VERSION 5.8 ;
BUSBITCHARS "[]" ;
DIVIDERCHAR "/" ;
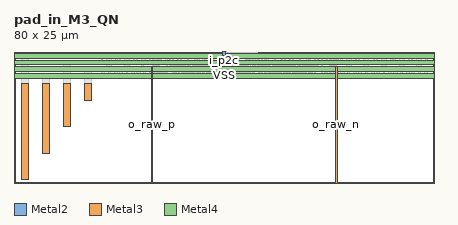
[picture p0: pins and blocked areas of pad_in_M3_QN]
MACRO pad_in_M3_QN
  CLASS BLOCK ;
  FOREIGN pad_in_M3_QN 0 0 ;
  ORIGIN 0.000 0.000 ;
  SIZE 80.000 BY 25.000 ;
  SYMMETRY X Y R90 ;
  PIN i_p2c
    DIRECTION INPUT ;
    PORT
      LAYER Metal2 ;
        RECT 39.725 24.200 40.225 25.000 ;
    END
  END i_p2c
  PIN i_clk_p
    DIRECTION INPUT ;
    PORT
      LAYER Metal3 ;
        RECT 9.500 10.700 10.700 19.000 ;
      LAYER Metal4 ;
        RECT 0.000 22.500 80.000 23.300 ;
    END
  END i_clk_p
  PIN i_clk_n
    DIRECTION INPUT ;
    PORT
      LAYER Metal3 ;
        RECT 13.500 15.700 14.700 19.000 ;
      LAYER Metal4 ;
        RECT 0.000 21.300 80.000 22.100 ;
    END
  END i_clk_n
  PIN o_raw_p
    DIRECTION OUTPUT ;
    PORT
      LAYER Metal3 ;
        RECT 26.110 0.000 26.410 22.275 ;
    END
  END o_raw_p
  PIN o_raw_n
    DIRECTION OUTPUT ;
    PORT
      LAYER Metal3 ;
        RECT 61.270 0.000 61.570 22.275 ;
    END
  END o_raw_n
  PIN VDD
    DIRECTION INOUT ;
    USE POWER ;
    PORT
      LAYER Metal3 ;
        RECT 1.500 0.700 2.700 19.000 ;
      LAYER Metal4 ;
        RECT 0.000 23.780 80.000 24.580 ;
    END
  END VDD
  PIN VSS
    DIRECTION INOUT ;
    USE GROUND ;
    PORT
      LAYER Metal3 ;
        RECT 5.500 5.700 6.700 19.000 ;
      LAYER Metal4 ;
        RECT 0.000 20.000 80.000 20.800 ;
    END
  END VSS
  OBS
    LAYER Metal1 ;
      RECT 16.480 20.180 79.840 20.620 ;
      RECT 47.790 22.140 48.560 22.440 ;
      RECT 16.480 23.960 79.840 24.400 ;
      RECT 63.300 21.875 64.235 23.960 ;
      RECT 65.615 20.620 66.250 21.390 ;
      RECT 68.025 20.620 68.635 21.390 ;
      RECT 68.975 20.620 69.610 21.390 ;
      RECT 71.385 20.620 71.995 21.390 ;
      RECT 72.335 20.620 72.970 21.390 ;
      RECT 74.745 20.620 75.355 21.390 ;
      RECT 75.695 20.620 76.330 21.390 ;
      RECT 78.105 20.620 78.715 21.390 ;
      RECT 66.970 20.620 67.275 21.430 ;
      RECT 70.330 20.620 70.635 21.430 ;
      RECT 73.690 20.620 73.995 21.430 ;
      RECT 77.050 20.620 77.355 21.430 ;
      RECT 64.665 21.390 64.915 22.210 ;
      RECT 65.960 21.390 66.250 22.210 ;
      RECT 68.025 21.390 68.275 22.210 ;
      RECT 69.320 21.390 69.610 22.210 ;
      RECT 71.385 21.390 71.635 22.210 ;
      RECT 72.680 21.390 72.970 22.210 ;
      RECT 74.745 21.390 74.995 22.210 ;
      RECT 76.040 21.390 76.330 22.210 ;
      RECT 78.105 21.390 78.355 22.210 ;
      RECT 64.665 20.620 65.275 21.390 ;
      RECT 65.025 22.610 65.285 23.960 ;
      RECT 65.625 22.605 65.885 23.960 ;
      RECT 66.660 21.875 67.595 23.960 ;
      RECT 68.385 22.610 68.645 23.960 ;
      RECT 68.985 22.605 69.245 23.960 ;
      RECT 70.020 21.875 70.955 23.960 ;
      RECT 71.745 22.610 72.005 23.960 ;
      RECT 72.345 22.605 72.605 23.960 ;
      RECT 73.380 21.875 74.315 23.960 ;
      RECT 75.105 22.610 75.365 23.960 ;
      RECT 75.705 22.605 75.965 23.960 ;
      RECT 76.740 21.875 77.675 23.960 ;
      RECT 78.465 22.610 78.725 23.960 ;
      RECT 50.380 21.695 50.540 22.415 ;
      RECT 55.180 21.695 55.340 22.415 ;
      RECT 56.000 22.340 56.260 22.415 ;
      RECT 55.180 22.415 56.260 22.540 ;
      RECT 54.360 22.540 56.260 22.590 ;
      RECT 56.000 22.590 56.260 22.600 ;
      RECT 49.220 22.140 50.200 22.300 ;
      RECT 54.020 22.140 55.000 22.300 ;
      RECT 58.490 21.610 58.680 22.550 ;
      RECT 48.740 21.940 48.900 23.040 ;
      RECT 53.540 21.940 53.700 23.040 ;
      RECT 61.075 22.240 61.335 22.395 ;
      RECT 51.640 21.820 51.800 22.800 ;
      RECT 52.480 22.140 53.360 22.440 ;
      RECT 56.440 21.820 56.600 22.800 ;
      RECT 57.280 22.140 58.060 22.440 ;
      RECT 60.055 22.565 60.315 23.530 ;
      RECT 61.075 22.565 61.335 23.530 ;
      RECT 56.790 22.440 57.090 22.740 ;
      RECT 58.490 22.550 59.295 22.820 ;
      RECT 59.035 22.820 59.295 23.170 ;
      RECT 56.280 22.800 56.600 22.940 ;
      RECT 56.280 22.940 56.540 23.700 ;
      RECT 60.055 22.395 61.335 22.565 ;
      RECT 57.280 22.440 57.440 23.340 ;
      RECT 57.220 23.340 57.480 23.700 ;
      RECT 57.780 23.400 58.040 23.960 ;
      RECT 58.525 23.040 58.785 23.960 ;
      RECT 59.545 22.480 59.805 23.960 ;
      RECT 60.565 22.890 60.825 23.960 ;
      RECT 61.585 22.515 61.845 23.960 ;
      RECT 62.265 22.605 62.525 23.960 ;
      RECT 49.540 23.200 49.840 23.270 ;
      RECT 54.360 22.510 54.620 22.540 ;
      RECT 54.340 22.970 54.640 23.040 ;
      RECT 53.540 23.040 54.640 23.200 ;
      RECT 54.340 23.200 54.640 23.270 ;
      RECT 49.560 22.510 49.820 22.540 ;
      RECT 50.380 22.415 51.460 22.540 ;
      RECT 49.560 22.540 51.460 22.590 ;
      RECT 54.360 22.590 55.340 22.700 ;
      RECT 54.360 22.700 54.620 22.770 ;
      RECT 51.480 22.800 51.800 22.940 ;
      RECT 51.480 22.940 51.740 23.700 ;
      RECT 54.800 22.700 55.340 22.840 ;
      RECT 52.480 22.440 52.640 23.340 ;
      RECT 52.420 23.340 52.680 23.700 ;
      RECT 51.200 22.590 51.460 22.600 ;
      RECT 49.220 22.300 49.380 22.540 ;
      RECT 49.080 22.540 49.380 22.860 ;
      RECT 49.560 22.590 50.540 22.700 ;
      RECT 54.020 22.300 54.180 22.540 ;
      RECT 53.880 22.540 54.180 22.860 ;
      RECT 48.180 23.130 48.440 23.960 ;
      RECT 49.560 23.450 49.820 23.960 ;
      RECT 50.940 23.130 51.200 23.960 ;
      RECT 52.980 23.130 53.240 23.960 ;
      RECT 54.360 23.450 54.620 23.960 ;
      RECT 55.740 23.130 56.000 23.960 ;
      RECT 49.560 22.700 49.820 22.770 ;
      RECT 50.000 22.700 50.540 22.840 ;
      RECT 51.990 22.440 52.290 22.740 ;
      RECT 51.200 22.340 51.460 22.415 ;
      RECT 49.540 22.970 49.840 23.040 ;
      RECT 48.740 23.040 49.840 23.200 ;
      RECT 50.270 21.350 50.540 21.695 ;
      RECT 55.070 21.350 55.340 21.695 ;
      RECT 48.310 21.680 48.570 21.780 ;
      RECT 48.310 21.780 48.900 21.940 ;
      RECT 54.050 21.350 54.210 22.140 ;
      RECT 54.740 22.040 55.000 22.140 ;
      RECT 48.670 21.050 48.970 21.500 ;
      RECT 51.360 21.030 51.620 21.520 ;
      RECT 51.360 21.520 51.660 21.620 ;
      RECT 51.360 21.620 51.800 21.820 ;
      RECT 50.720 21.915 51.020 22.215 ;
      RECT 49.250 21.350 49.410 22.140 ;
      RECT 53.110 21.680 53.370 21.780 ;
      RECT 52.380 21.030 52.640 21.490 ;
      RECT 52.480 21.490 52.640 22.140 ;
      RECT 53.110 21.780 53.700 21.940 ;
      RECT 49.940 22.040 50.200 22.140 ;
      RECT 55.520 21.915 55.820 22.215 ;
      RECT 51.870 20.620 52.130 21.390 ;
      RECT 53.470 20.850 55.790 21.050 ;
      RECT 48.180 20.620 48.440 21.500 ;
      RECT 52.980 20.620 53.240 21.500 ;
      RECT 53.470 21.050 53.770 21.500 ;
      RECT 55.530 21.050 55.790 21.650 ;
      RECT 49.710 21.240 49.970 21.690 ;
      RECT 54.510 21.240 54.770 21.690 ;
      RECT 48.670 20.850 50.990 21.050 ;
      RECT 50.730 21.050 50.990 21.650 ;
      RECT 59.650 21.940 60.400 22.200 ;
      RECT 63.610 20.620 63.915 21.430 ;
      RECT 59.105 21.010 59.705 21.270 ;
      RECT 56.160 21.030 56.420 21.520 ;
      RECT 56.160 21.520 56.460 21.620 ;
      RECT 56.160 21.620 56.600 21.820 ;
      RECT 60.565 20.620 60.825 21.270 ;
      RECT 58.930 21.875 59.380 22.285 ;
      RECT 58.490 21.040 58.835 21.450 ;
      RECT 56.670 20.620 56.930 21.390 ;
      RECT 62.255 20.620 62.890 21.390 ;
      RECT 57.180 21.030 57.440 21.490 ;
      RECT 57.280 21.490 57.440 22.140 ;
      RECT 58.490 21.450 59.815 21.610 ;
      RECT 61.585 20.620 61.845 21.610 ;
      RECT 62.600 21.390 62.890 22.210 ;
      RECT 59.650 21.610 59.815 21.940 ;
      RECT 60.055 21.045 60.315 21.465 ;
      RECT 61.075 21.005 61.335 21.465 ;
      RECT 60.055 21.465 61.335 21.625 ;
      RECT 61.075 21.625 61.335 21.925 ;
      RECT 59.275 20.620 59.535 21.010 ;
      RECT 61.075 21.925 61.760 22.240 ;
      RECT 31.420 22.415 32.500 22.540 ;
      RECT 31.420 22.540 33.320 22.590 ;
      RECT 31.890 20.850 34.210 21.050 ;
      RECT 33.980 21.940 34.140 23.040 ;
      RECT 38.780 21.940 38.940 23.040 ;
      RECT 43.580 21.940 43.740 23.040 ;
      RECT 45.370 22.105 47.110 22.405 ;
      RECT 40.190 22.440 40.490 22.740 ;
      RECT 32.340 21.695 32.500 22.415 ;
      RECT 37.140 21.695 37.300 22.415 ;
      RECT 34.320 22.140 35.200 22.440 ;
      RECT 35.880 21.820 36.040 22.800 ;
      RECT 39.120 22.140 40.000 22.440 ;
      RECT 40.680 21.820 40.840 22.800 ;
      RECT 43.920 22.140 44.690 22.440 ;
      RECT 44.980 21.820 45.140 22.570 ;
      RECT 47.340 21.820 47.500 22.570 ;
      RECT 41.940 21.695 42.100 22.415 ;
      RECT 32.680 22.140 33.660 22.300 ;
      RECT 37.480 22.140 38.460 22.300 ;
      RECT 42.280 22.140 43.260 22.300 ;
      RECT 42.640 22.970 42.940 23.040 ;
      RECT 44.530 22.440 44.690 23.320 ;
      RECT 44.530 23.320 44.860 23.470 ;
      RECT 44.600 23.470 44.860 23.700 ;
      RECT 42.640 23.040 43.740 23.200 ;
      RECT 44.870 22.570 45.170 22.690 ;
      RECT 44.870 22.690 45.370 22.870 ;
      RECT 45.110 22.870 45.370 23.700 ;
      RECT 42.640 23.200 42.940 23.270 ;
      RECT 47.310 22.570 47.610 22.690 ;
      RECT 47.110 22.690 47.610 22.870 ;
      RECT 47.110 22.870 47.370 23.700 ;
      RECT 47.790 22.440 47.950 23.320 ;
      RECT 47.620 23.320 47.950 23.470 ;
      RECT 47.620 23.470 47.880 23.700 ;
      RECT 41.020 22.340 41.280 22.415 ;
      RECT 43.100 22.300 43.260 22.540 ;
      RECT 41.020 22.415 42.100 22.540 ;
      RECT 42.660 22.510 42.920 22.540 ;
      RECT 41.020 22.540 42.920 22.590 ;
      RECT 41.020 22.590 41.280 22.600 ;
      RECT 41.940 22.590 42.920 22.700 ;
      RECT 42.660 22.700 42.920 22.770 ;
      RECT 41.940 22.700 42.480 22.840 ;
      RECT 41.280 23.130 41.540 23.960 ;
      RECT 42.660 23.450 42.920 23.960 ;
      RECT 44.040 23.130 44.300 23.960 ;
      RECT 45.650 23.410 45.910 23.960 ;
      RECT 46.570 23.410 46.830 23.960 ;
      RECT 43.100 22.540 43.400 22.860 ;
      RECT 40.680 22.800 41.000 22.940 ;
      RECT 40.740 22.940 41.000 23.700 ;
      RECT 39.840 22.440 40.000 23.340 ;
      RECT 39.800 23.340 40.060 23.700 ;
      RECT 37.860 22.510 38.120 22.540 ;
      RECT 36.220 22.540 38.120 22.590 ;
      RECT 36.220 22.590 36.480 22.600 ;
      RECT 37.140 22.590 38.120 22.700 ;
      RECT 37.860 22.700 38.120 22.770 ;
      RECT 37.140 22.700 37.680 22.840 ;
      RECT 33.040 23.040 34.140 23.200 ;
      RECT 33.040 23.200 33.340 23.270 ;
      RECT 33.060 22.510 33.320 22.540 ;
      RECT 37.840 22.970 38.140 23.040 ;
      RECT 32.340 22.590 33.320 22.700 ;
      RECT 33.060 22.700 33.320 22.770 ;
      RECT 32.340 22.700 32.880 22.840 ;
      RECT 36.220 22.340 36.480 22.415 ;
      RECT 33.040 22.970 33.340 23.040 ;
      RECT 33.060 23.450 33.320 23.960 ;
      RECT 34.440 23.130 34.700 23.960 ;
      RECT 36.480 23.130 36.740 23.960 ;
      RECT 37.860 23.450 38.120 23.960 ;
      RECT 39.240 23.130 39.500 23.960 ;
      RECT 37.840 23.040 38.940 23.200 ;
      RECT 35.040 22.440 35.200 23.340 ;
      RECT 35.000 23.340 35.260 23.700 ;
      RECT 35.390 22.440 35.690 22.740 ;
      RECT 35.880 22.800 36.200 22.940 ;
      RECT 35.940 22.940 36.200 23.700 ;
      RECT 33.500 22.300 33.660 22.540 ;
      RECT 33.500 22.540 33.800 22.860 ;
      RECT 36.220 22.415 37.300 22.540 ;
      RECT 38.300 22.300 38.460 22.540 ;
      RECT 38.300 22.540 38.600 22.860 ;
      RECT 37.840 23.200 38.140 23.270 ;
      RECT 36.690 20.850 39.010 21.050 ;
      RECT 39.840 21.030 40.100 21.490 ;
      RECT 35.550 20.620 35.810 21.390 ;
      RECT 39.840 21.490 40.000 22.140 ;
      RECT 38.710 21.050 39.010 21.500 ;
      RECT 36.690 21.050 36.950 21.650 ;
      RECT 32.910 21.240 33.170 21.690 ;
      RECT 37.140 21.350 37.410 21.695 ;
      RECT 39.110 21.680 39.370 21.780 ;
      RECT 38.780 21.780 39.370 21.940 ;
      RECT 35.040 21.030 35.300 21.490 ;
      RECT 35.040 21.490 35.200 22.140 ;
      RECT 36.660 21.915 36.960 22.215 ;
      RECT 33.910 21.050 34.210 21.500 ;
      RECT 34.440 20.620 34.700 21.500 ;
      RECT 39.240 20.620 39.500 21.500 ;
      RECT 32.680 22.040 32.940 22.140 ;
      RECT 33.470 21.350 33.630 22.140 ;
      RECT 32.340 21.350 32.610 21.695 ;
      RECT 37.710 21.240 37.970 21.690 ;
      RECT 36.060 21.030 36.320 21.520 ;
      RECT 37.480 22.040 37.740 22.140 ;
      RECT 38.270 21.350 38.430 22.140 ;
      RECT 36.020 21.520 36.320 21.620 ;
      RECT 35.880 21.620 36.320 21.820 ;
      RECT 34.310 21.680 34.570 21.780 ;
      RECT 33.980 21.780 34.570 21.940 ;
      RECT 40.820 21.520 41.120 21.620 ;
      RECT 40.680 21.620 41.120 21.820 ;
      RECT 43.580 21.780 44.170 21.940 ;
      RECT 43.510 21.050 43.810 21.500 ;
      RECT 47.650 21.030 47.910 21.350 ;
      RECT 47.650 21.350 47.950 21.460 ;
      RECT 47.790 21.460 47.950 22.140 ;
      RECT 41.490 21.050 41.750 21.650 ;
      RECT 44.570 21.030 44.830 21.350 ;
      RECT 44.530 21.350 44.830 21.460 ;
      RECT 44.530 21.460 44.690 22.140 ;
      RECT 41.460 21.915 41.760 22.215 ;
      RECT 47.140 20.620 47.400 21.390 ;
      RECT 42.510 21.240 42.770 21.690 ;
      RECT 40.350 20.620 40.610 21.390 ;
      RECT 44.040 20.620 44.300 21.500 ;
      RECT 45.590 21.030 45.850 21.520 ;
      RECT 45.550 21.520 45.850 21.620 ;
      RECT 41.940 21.350 42.210 21.695 ;
      RECT 44.980 21.620 45.850 21.820 ;
      RECT 41.490 20.850 43.810 21.050 ;
      RECT 45.080 20.620 45.340 21.390 ;
      RECT 43.910 21.680 44.170 21.780 ;
      RECT 40.860 21.030 41.120 21.520 ;
      RECT 46.630 21.030 46.890 21.520 ;
      RECT 46.630 21.520 46.930 21.620 ;
      RECT 42.280 22.040 42.540 22.140 ;
      RECT 43.070 21.350 43.230 22.140 ;
      RECT 46.630 21.620 47.500 21.820 ;
      RECT 31.860 21.915 32.160 22.215 ;
      RECT 30.590 22.440 30.890 22.740 ;
      RECT 20.360 21.390 20.650 22.210 ;
      RECT 30.240 21.030 30.500 21.490 ;
      RECT 30.240 21.490 30.400 22.140 ;
      RECT 29.620 22.140 30.400 22.440 ;
      RECT 30.240 22.440 30.400 23.340 ;
      RECT 30.200 23.340 30.460 23.700 ;
      RECT 28.145 20.620 28.405 21.010 ;
      RECT 31.260 21.030 31.520 21.520 ;
      RECT 26.855 20.620 27.115 21.270 ;
      RECT 18.010 20.620 18.315 21.430 ;
      RECT 21.370 20.620 21.675 21.430 ;
      RECT 27.975 21.010 28.575 21.270 ;
      RECT 24.265 21.870 24.605 22.620 ;
      RECT 16.665 22.605 16.925 23.960 ;
      RECT 17.700 21.875 18.635 23.960 ;
      RECT 19.425 22.610 19.685 23.960 ;
      RECT 20.025 22.605 20.285 23.960 ;
      RECT 21.060 21.875 21.995 23.960 ;
      RECT 22.785 22.610 23.045 23.960 ;
      RECT 23.330 22.620 23.600 23.960 ;
      RECT 24.265 22.620 24.990 23.960 ;
      RECT 25.835 22.515 26.095 23.960 ;
      RECT 26.855 22.890 27.115 23.960 ;
      RECT 27.875 22.480 28.135 23.960 ;
      RECT 28.895 23.040 29.155 23.960 ;
      RECT 29.640 23.400 29.900 23.960 ;
      RECT 31.680 23.130 31.940 23.960 ;
      RECT 31.220 21.520 31.520 21.620 ;
      RECT 31.080 21.620 31.520 21.820 ;
      RECT 31.080 21.820 31.240 22.800 ;
      RECT 31.080 22.800 31.400 22.940 ;
      RECT 31.140 22.940 31.400 23.700 ;
      RECT 22.425 21.390 22.675 22.210 ;
      RECT 28.845 21.040 29.190 21.450 ;
      RECT 27.865 21.450 29.190 21.610 ;
      RECT 27.865 21.610 28.030 21.940 ;
      RECT 31.420 22.340 31.680 22.415 ;
      RECT 27.280 21.940 28.030 22.200 ;
      RECT 31.890 21.050 32.150 21.650 ;
      RECT 23.330 20.620 24.055 21.335 ;
      RECT 24.710 20.620 24.990 21.335 ;
      RECT 29.000 21.610 29.190 22.550 ;
      RECT 26.345 21.005 26.605 21.465 ;
      RECT 27.365 21.045 27.625 21.465 ;
      RECT 16.655 20.620 17.290 21.390 ;
      RECT 19.065 20.620 19.675 21.390 ;
      RECT 25.835 20.620 26.095 21.610 ;
      RECT 20.015 20.620 20.650 21.390 ;
      RECT 23.730 21.335 24.055 22.205 ;
      RECT 17.000 21.390 17.290 22.210 ;
      RECT 19.065 21.390 19.315 22.210 ;
      RECT 26.345 21.465 27.625 21.625 ;
      RECT 26.345 21.625 26.605 21.925 ;
      RECT 25.920 21.925 26.605 22.240 ;
      RECT 26.345 22.240 26.605 22.395 ;
      RECT 26.345 22.395 27.625 22.565 ;
      RECT 26.345 22.565 26.605 23.530 ;
      RECT 27.365 22.565 27.625 23.530 ;
      RECT 28.385 22.550 29.190 22.820 ;
      RECT 28.385 22.820 28.645 23.170 ;
      RECT 31.420 22.590 31.680 22.600 ;
      RECT 22.425 20.620 23.035 21.390 ;
      RECT 28.300 21.875 28.750 22.285 ;
      RECT 30.750 20.620 31.010 21.390 ;
    LAYER Metal2 ;
      RECT 46.635 21.595 49.390 21.815 ;
      RECT 56.365 20.205 56.755 20.595 ;
      RECT 62.685 20.205 63.075 20.595 ;
      RECT 64.385 20.205 64.775 20.595 ;
      RECT 66.045 20.205 66.435 20.595 ;
      RECT 67.745 20.205 68.135 20.595 ;
      RECT 69.405 20.205 69.795 20.595 ;
      RECT 71.105 20.205 71.495 20.595 ;
      RECT 72.765 20.205 73.155 20.595 ;
      RECT 74.465 20.205 74.855 20.595 ;
      RECT 76.125 20.205 76.515 20.595 ;
      RECT 77.825 20.205 78.215 20.595 ;
      RECT 49.690 20.250 49.990 20.550 ;
      RECT 49.690 20.550 49.890 21.360 ;
      RECT 49.690 21.360 49.990 21.645 ;
      RECT 54.490 20.250 54.790 20.550 ;
      RECT 54.490 20.550 54.690 21.360 ;
      RECT 54.490 21.360 54.790 21.645 ;
      RECT 51.565 20.205 51.955 20.595 ;
      RECT 49.170 21.815 49.390 21.920 ;
      RECT 49.170 21.920 51.015 22.120 ;
      RECT 50.725 22.120 51.015 22.210 ;
      RECT 51.365 21.525 51.655 21.595 ;
      RECT 51.365 21.595 54.190 21.815 ;
      RECT 53.970 21.815 54.190 21.920 ;
      RECT 53.970 21.920 55.815 22.120 ;
      RECT 55.525 22.120 55.815 22.210 ;
      RECT 57.760 21.320 58.060 21.420 ;
      RECT 56.165 21.525 56.455 21.595 ;
      RECT 57.760 21.420 59.255 21.595 ;
      RECT 56.165 21.595 59.255 21.720 ;
      RECT 56.165 21.720 58.060 21.815 ;
      RECT 59.055 21.720 59.255 22.225 ;
      RECT 61.225 21.885 61.615 22.275 ;
      RECT 51.990 22.440 52.290 22.540 ;
      RECT 49.080 22.540 52.290 22.740 ;
      RECT 49.080 22.740 49.380 22.840 ;
      RECT 56.790 22.440 57.090 22.540 ;
      RECT 53.880 22.540 57.090 22.740 ;
      RECT 53.880 22.740 54.180 22.840 ;
      RECT 49.545 22.975 50.410 23.265 ;
      RECT 54.345 22.975 55.210 23.265 ;
      RECT 50.365 23.985 50.755 24.375 ;
      RECT 55.165 23.985 55.555 24.375 ;
      RECT 62.685 23.985 63.075 24.375 ;
      RECT 64.385 23.985 64.775 24.375 ;
      RECT 66.045 23.985 66.435 24.375 ;
      RECT 67.745 23.985 68.135 24.375 ;
      RECT 69.405 23.985 69.795 24.375 ;
      RECT 71.105 23.985 71.495 24.375 ;
      RECT 72.765 23.985 73.155 24.375 ;
      RECT 74.465 23.985 74.855 24.375 ;
      RECT 76.125 23.985 76.515 24.375 ;
      RECT 77.825 23.985 78.215 24.375 ;
      RECT 20.445 20.205 20.835 20.595 ;
      RECT 32.890 20.250 33.190 20.550 ;
      RECT 32.990 20.550 33.190 21.360 ;
      RECT 32.890 21.360 33.190 21.645 ;
      RECT 37.690 20.250 37.990 20.550 ;
      RECT 37.790 20.550 37.990 21.360 ;
      RECT 37.690 21.360 37.990 21.645 ;
      RECT 29.620 21.320 29.920 21.420 ;
      RECT 28.425 21.420 29.920 21.595 ;
      RECT 31.225 21.525 31.515 21.595 ;
      RECT 28.425 21.595 31.515 21.720 ;
      RECT 29.620 21.720 31.515 21.815 ;
      RECT 28.425 21.720 28.625 22.225 ;
      RECT 42.490 20.250 42.790 20.550 ;
      RECT 42.590 20.550 42.790 21.360 ;
      RECT 42.490 21.360 42.790 21.645 ;
      RECT 22.145 20.205 22.535 20.595 ;
      RECT 30.925 20.205 31.315 20.595 ;
      RECT 35.725 20.205 36.115 20.595 ;
      RECT 26.065 21.885 26.455 22.275 ;
      RECT 40.525 20.205 40.915 20.595 ;
      RECT 30.590 22.440 30.890 22.540 ;
      RECT 30.590 22.540 33.800 22.740 ;
      RECT 33.500 22.740 33.800 22.840 ;
      RECT 35.390 22.440 35.690 22.540 ;
      RECT 35.390 22.540 38.600 22.740 ;
      RECT 38.300 22.740 38.600 22.840 ;
      RECT 40.190 22.440 40.490 22.540 ;
      RECT 40.190 22.540 43.400 22.740 ;
      RECT 43.100 22.740 43.400 22.840 ;
      RECT 45.085 20.205 45.475 20.595 ;
      RECT 47.005 20.205 47.395 20.595 ;
      RECT 36.025 21.525 36.315 21.595 ;
      RECT 33.490 21.595 36.315 21.815 ;
      RECT 33.490 21.815 33.710 21.920 ;
      RECT 31.865 21.920 33.710 22.120 ;
      RECT 32.470 22.975 33.335 23.265 ;
      RECT 37.270 22.975 38.135 23.265 ;
      RECT 42.070 22.975 42.935 23.265 ;
      RECT 31.865 22.120 32.155 22.210 ;
      RECT 40.825 21.525 41.115 21.595 ;
      RECT 17.085 23.985 17.475 24.375 ;
      RECT 18.785 23.985 19.175 24.375 ;
      RECT 20.445 23.985 20.835 24.375 ;
      RECT 22.145 23.985 22.535 24.375 ;
      RECT 32.125 23.985 32.515 24.375 ;
      RECT 36.925 23.985 37.315 24.375 ;
      RECT 41.725 23.985 42.115 24.375 ;
      RECT 45.085 23.985 45.475 24.375 ;
      RECT 47.005 23.985 47.395 24.375 ;
      RECT 38.290 21.595 41.115 21.815 ;
      RECT 38.290 21.815 38.510 21.920 ;
      RECT 36.665 21.920 38.510 22.120 ;
      RECT 36.665 22.120 36.955 22.210 ;
      RECT 45.555 21.525 45.845 21.595 ;
      RECT 43.090 21.595 45.845 21.815 ;
      RECT 43.090 21.815 43.310 21.920 ;
      RECT 41.465 21.920 43.310 22.120 ;
      RECT 41.465 22.120 41.755 22.210 ;
      RECT 46.635 21.525 46.925 21.595 ;
      RECT 17.085 20.205 17.475 20.595 ;
      RECT 18.785 20.205 19.175 20.595 ;
      RECT 40.225 24.200 40.410 24.600 ;
      RECT 46.090 21.955 46.390 24.600 ;
      RECT 40.225 24.600 46.390 24.900 ;
      RECT 40.225 24.900 40.410 25.000 ;
    LAYER Metal3 ;
      RECT 17.085 20.205 17.475 20.595 ;
      RECT 18.785 20.205 19.175 20.595 ;
      RECT 20.445 20.205 20.835 20.595 ;
      RECT 22.145 20.205 22.535 20.595 ;
      RECT 30.925 20.205 31.315 20.595 ;
      RECT 35.725 20.205 36.115 20.595 ;
      RECT 40.525 20.205 40.915 20.595 ;
      RECT 45.085 20.205 45.475 20.595 ;
      RECT 47.005 20.205 47.395 20.595 ;
      RECT 51.565 20.205 51.955 20.595 ;
      RECT 56.365 20.205 56.755 20.595 ;
      RECT 62.685 20.205 63.075 20.595 ;
      RECT 64.385 20.205 64.775 20.595 ;
      RECT 66.045 20.205 66.435 20.595 ;
      RECT 67.745 20.205 68.135 20.595 ;
      RECT 69.405 20.205 69.795 20.595 ;
      RECT 71.105 20.205 71.495 20.595 ;
      RECT 72.765 20.205 73.155 20.595 ;
      RECT 74.465 20.205 74.855 20.595 ;
      RECT 76.125 20.205 76.515 20.595 ;
      RECT 77.825 20.205 78.215 20.595 ;
      RECT 5.500 19.000 6.700 20.700 ;
      RECT 13.500 19.000 14.700 22.000 ;
      RECT 9.500 19.000 10.700 23.200 ;
      RECT 32.705 21.505 33.095 21.895 ;
      RECT 32.750 21.895 33.050 23.315 ;
      RECT 37.505 22.925 37.895 23.315 ;
      RECT 42.305 21.505 42.695 21.895 ;
      RECT 42.350 21.895 42.650 23.315 ;
      RECT 49.785 22.925 50.175 23.315 ;
      RECT 54.585 21.505 54.975 21.895 ;
      RECT 54.630 21.895 54.930 23.315 ;
      RECT 17.085 23.985 17.475 24.375 ;
      RECT 18.785 23.985 19.175 24.375 ;
      RECT 20.445 23.985 20.835 24.375 ;
      RECT 22.145 23.985 22.535 24.375 ;
      RECT 32.125 23.985 32.515 24.375 ;
      RECT 36.925 23.985 37.315 24.375 ;
      RECT 41.725 23.985 42.115 24.375 ;
      RECT 45.085 23.985 45.475 24.375 ;
      RECT 47.005 23.985 47.395 24.375 ;
      RECT 50.365 23.985 50.755 24.375 ;
      RECT 55.165 23.985 55.555 24.375 ;
      RECT 62.685 23.985 63.075 24.375 ;
      RECT 64.385 23.985 64.775 24.375 ;
      RECT 66.045 23.985 66.435 24.375 ;
      RECT 67.745 23.985 68.135 24.375 ;
      RECT 69.405 23.985 69.795 24.375 ;
      RECT 71.105 23.985 71.495 24.375 ;
      RECT 72.765 23.985 73.155 24.375 ;
      RECT 74.465 23.985 74.855 24.375 ;
      RECT 76.125 23.985 76.515 24.375 ;
      RECT 77.825 23.985 78.215 24.375 ;
      RECT 1.500 19.000 2.700 24.480 ;
  END
END pad_in_M3_QN

END LIBRARY
